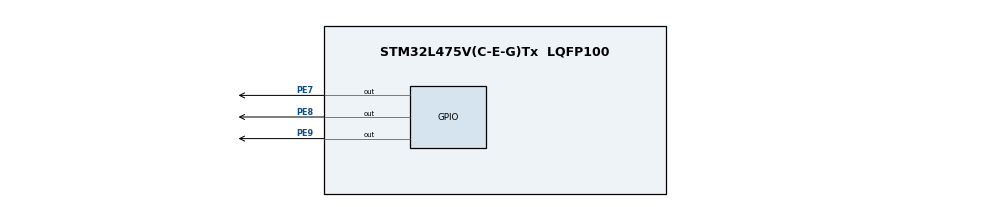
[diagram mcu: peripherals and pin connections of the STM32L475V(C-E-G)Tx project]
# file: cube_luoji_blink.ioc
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Mcu.Family=STM32L4
Mcu.Name=STM32L475V(C-E-G)Tx
Mcu.Package=LQFP100
NVIC.PriorityGroup=NVIC_PRIORITYGROUP_4
PE7.GPIO_PuPd=GPIO_PULLUP
PE7.GPIO_Speed=GPIO_SPEED_FREQ_HIGH
PE7.PinState=GPIO_PIN_SET
PE7.Signal=GPIO_Output
PE8.GPIO_ModeDefaultOutputPP=GPIO_MODE_OUTPUT_PP
PE8.GPIO_PuPd=GPIO_PULLUP
PE8.GPIO_Speed=GPIO_SPEED_FREQ_HIGH
PE8.PinState=GPIO_PIN_SET
PE8.Signal=GPIO_Output
PE9.GPIO_PuPd=GPIO_PULLUP
PE9.GPIO_Speed=GPIO_SPEED_FREQ_HIGH
PE9.PinState=GPIO_PIN_SET
PE9.Signal=GPIO_Output
PH0-OSC_IN\ (PH0).Mode=HSE-External-Oscillator
PH0-OSC_IN\ (PH0).Signal=RCC_OSC_IN
PH1-OSC_OUT\ (PH1).Mode=HSE-External-Oscillator
PH1-OSC_OUT\ (PH1).Signal=RCC_OSC_OUT
ProjectManager.HeapSize=0x200
ProjectManager.StackSize=0x400
ProjectManager.TargetToolchain=MDK-ARM V5
RCC.ADCFreq_Value=32000000
RCC.AHBFreq_Value=32000000
RCC.APB1Freq_Value=32000000
RCC.APB1TimFreq_Value=32000000
RCC.APB2Freq_Value=32000000
RCC.APB2TimFreq_Value=32000000
RCC.CortexFreq_Value=32000000
RCC.HCLKFreq_Value=32000000
RCC.HSE_VALUE=8000000
RCC.HSI_VALUE=16000000
RCC.LSE_VALUE=32768
RCC.MSI_VALUE=4000000
RCC.PLLSourceVirtual=RCC_PLLSOURCE_HSE
RCC.SYSCLKFreq_VALUE=32000000
RCC.SYSCLKSource=RCC_SYSCLKSOURCE_PLLCLK
RCC.USBFreq_Value=32000000
RCC.VCOOutputFreq_Value=64000000
board=custom

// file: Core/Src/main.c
#include <rtthread.h>
/* USER CODE BEGIN Header */
/**
  ******************************************************************************
  * @file           : main.c
  * @brief          : Main program body
  ******************************************************************************
  * @attention
  *
  * <h2><center>&copy; Copyright (c) 2021 STMicroelectronics.
  * All rights reserved.</center></h2>
  *
  * This software component is licensed by ST under BSD 3-Clause license,
  * the "License"; You may not use this file except in compliance with the
  * License. You may obtain a copy of the License at:
  *                        opensource.org/licenses/BSD-3-Clause
  *
  ******************************************************************************
  */
/* USER CODE END Header */
#include "main.h"
#include <rtthread.h>

#define THREAD_PRIORITY         (RT_THREAD_PRIORITY_MAX -2)
#define THREAD_STACK_SIZE       512
#define THREAD_TIMESLICE        5

void MX_GPIO_Init(void);

static void thread1_entry(void *parameter){

 while (1)
  {
    /* USER CODE END WHILE */
				HAL_GPIO_WritePin(GPIOE, GPIO_PIN_9, GPIO_PIN_SET); 	//PE7 ?1
        rt_thread_delay(200);
        HAL_GPIO_WritePin(GPIOE, GPIO_PIN_9, GPIO_PIN_RESET);	//PE7 ?0
        rt_thread_delay(200);

    /* USER CODE BEGIN 3 */
  }
}
static rt_thread_t tid1 = RT_NULL;
void test_led_blink_thread(){

	tid1 = rt_thread_create("thread1",
                            thread1_entry,
														RT_NULL,
                            THREAD_STACK_SIZE,
                            THREAD_PRIORITY, THREAD_TIMESLICE);
	if (tid1 != RT_NULL){

		rt_thread_startup(tid1);
	}

}

ALIGN(RT_ALIGN_SIZE)
static char thread2_stack[1024];
static struct rt_thread thread2;
/* 线程2入口 */
static void thread2_entry(void *param)
{
    rt_uint32_t count = 0;

    /* 线程2拥有较高的优先级，以抢占线程1而获得执行 */
    for (count = 0; count < 10 ; count++)
    {
        /* 线程2打印计数值 */
        rt_kprintf("thread2 count: %d\n", count);
			rt_thread_delay(500);
    }
    rt_kprintf("thread2 exit\n");
    /* 线程2运行结束后也将自动被系统删除
    (线程控制块和线程栈依然在idle线程中释放) */
}

void test_static_mem(){
	rt_thread_init(&thread2,
										 "thread2",
										 thread2_entry,
										 RT_NULL,
										 &thread2_stack[0],
										 sizeof(thread2_stack),
										 THREAD_PRIORITY - 1, THREAD_TIMESLICE);
			rt_thread_startup(&thread2);
}

/**
  * @brief  The application entry point.
  * @retval int
  */
int main(void)
{
  /* USER CODE BEGIN 1 */

  /* USER CODE END 1 */

  /* MCU Configuration--------------------------------------------------------*/

  /* Reset of all peripherals, Initializes the Flash interface and the Systick. */
  //HAL_Init();

  /* USER CODE BEGIN Init */

  /* USER CODE END Init */

  /* Configure the system clock */
  //SystemClock_Config();

  /* USER CODE BEGIN SysInit */

  /* USER CODE END SysInit */

  /* Initialize all configured peripherals */
  MX_GPIO_Init();
  /* USER CODE BEGIN 2 */

  /* USER CODE END 2 */

  /* Infinite loop */
  /* USER CODE BEGIN WHILE */

	test_led_blink_thread();
	//test_static_mem();
	while(1){
		rt_thread_delay(200);

	}
	return 0;

  /* USER CODE END 3 */
}

void SystemClock_Config(void)
{
  RCC_OscInitTypeDef RCC_OscInitStruct = {0};
  RCC_ClkInitTypeDef RCC_ClkInitStruct = {0};

  /** Initializes the RCC Oscillators according to the specified parameters
  * in the RCC_OscInitTypeDef structure.
  */
  RCC_OscInitStruct.OscillatorType = RCC_OSCILLATORTYPE_HSE;
  RCC_OscInitStruct.HSEState = RCC_HSE_ON;
  RCC_OscInitStruct.PLL.PLLState = RCC_PLL_ON;
  RCC_OscInitStruct.PLL.PLLSource = RCC_PLLSOURCE_HSE;
  RCC_OscInitStruct.PLL.PLLM = 1;
  RCC_OscInitStruct.PLL.PLLN = 20;
  RCC_OscInitStruct.PLL.PLLP = RCC_PLLP_DIV7;
  RCC_OscInitStruct.PLL.PLLQ = RCC_PLLQ_DIV2;
  RCC_OscInitStruct.PLL.PLLR = RCC_PLLR_DIV2;
  if (HAL_RCC_OscConfig(&RCC_OscInitStruct) != HAL_OK)
  {
    Error_Handler();
  }
  /** Initializes the CPU, AHB and APB buses clocks
  */
  RCC_ClkInitStruct.ClockType = RCC_CLOCKTYPE_HCLK|RCC_CLOCKTYPE_SYSCLK
                              |RCC_CLOCKTYPE_PCLK1|RCC_CLOCKTYPE_PCLK2;
  RCC_ClkInitStruct.SYSCLKSource = RCC_SYSCLKSOURCE_PLLCLK;
  RCC_ClkInitStruct.AHBCLKDivider = RCC_SYSCLK_DIV1;
  RCC_ClkInitStruct.APB1CLKDivider = RCC_HCLK_DIV1;
  RCC_ClkInitStruct.APB2CLKDivider = RCC_HCLK_DIV1;

  if (HAL_RCC_ClockConfig(&RCC_ClkInitStruct, FLASH_LATENCY_1) != HAL_OK)
  {
    Error_Handler();
  }
  /** Configure the main internal regulator output voltage
  */
  if (HAL_PWREx_ControlVoltageScaling(PWR_REGULATOR_VOLTAGE_SCALE1) != HAL_OK)
  {
    Error_Handler();
  }
}

void MX_GPIO_Init(void)
{
  GPIO_InitTypeDef GPIO_InitStruct = {0};

  /* GPIO Ports Clock Enable */
  __HAL_RCC_GPIOH_CLK_ENABLE();
  __HAL_RCC_GPIOE_CLK_ENABLE();

  /*Configure GPIO pin Output Level */
  HAL_GPIO_WritePin(GPIOE, GPIO_PIN_7|GPIO_PIN_8|GPIO_PIN_9, GPIO_PIN_SET);

  /*Configure GPIO pins : PE7 PE8 PE9 */
  GPIO_InitStruct.Pin = GPIO_PIN_7|GPIO_PIN_8|GPIO_PIN_9;
  GPIO_InitStruct.Mode = GPIO_MODE_OUTPUT_PP;
  GPIO_InitStruct.Pull = GPIO_PULLUP;
  GPIO_InitStruct.Speed = GPIO_SPEED_FREQ_HIGH;
  HAL_GPIO_Init(GPIOE, &GPIO_InitStruct);

}

void Error_Handler(void)
{
  __disable_irq();
  while (1)
  {
  }
}

/************************ (C) COPYRIGHT STMicroelectronics *****END OF FILE****/
